VERSION 5.7 ;
  NOWIREEXTENSIONATPIN ON ;
  DIVIDERCHAR "/" ;
  BUSBITCHARS "[]" ;
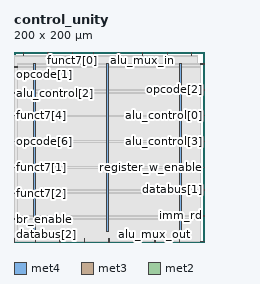
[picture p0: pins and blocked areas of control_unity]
MACRO control_unity
  CLASS BLOCK ;
  FOREIGN control_unity ;
  ORIGIN 0.000 0.000 ;
  SIZE 200.000 BY 200.000 ;
  PIN VGND
    USE GROUND ;
    PORT
      LAYER met4 ;
        RECT 97.840 10.640 99.440 187.920 ;
    END
  END VGND
  PIN VPWR
    USE POWER ;
    PORT
      LAYER met4 ;
        RECT 174.640 10.640 176.240 187.920 ;
    END
    PORT
      LAYER met4 ;
        RECT 21.040 10.640 22.640 187.920 ;
    END
  END VPWR
  PIN alu_control[0]
    PORT
      LAYER met3 ;
        RECT 196.000 132.640 200.000 133.240 ;
    END
  END alu_control[0]
  PIN alu_control[1]
    PORT
      LAYER met2 ;
        RECT 99.910 0.000 100.190 4.000 ;
    END
  END alu_control[1]
  PIN alu_control[2]
    PORT
      LAYER met3 ;
        RECT 0.000 156.440 4.000 157.040 ;
    END
  END alu_control[2]
  PIN alu_control[3]
    PORT
      LAYER met3 ;
        RECT 196.000 105.440 200.000 106.040 ;
    END
  END alu_control[3]
  PIN alu_mux_in
    PORT
      LAYER met2 ;
        RECT 135.330 196.000 135.610 200.000 ;
    END
  END alu_mux_in
  PIN alu_mux_out
    PORT
      LAYER met2 ;
        RECT 148.210 0.000 148.490 4.000 ;
    END
  END alu_mux_out
  PIN br_enable
    PORT
      LAYER met3 ;
        RECT 0.000 23.840 4.000 24.440 ;
    END
  END br_enable
  PIN br_mux_inv
    PORT
      LAYER met3 ;
        RECT 196.000 187.040 200.000 187.640 ;
    END
  END br_mux_inv
  PIN databus[0]
    PORT
      LAYER met2 ;
        RECT 161.090 196.000 161.370 200.000 ;
    END
  END databus[0]
  PIN databus[1]
    PORT
      LAYER met3 ;
        RECT 196.000 54.440 200.000 55.040 ;
    END
  END databus[1]
  PIN databus[2]
    PORT
      LAYER met2 ;
        RECT 0.090 0.000 0.370 4.000 ;
    END
  END databus[2]
  PIN funct3[0]
    PORT
      LAYER met2 ;
        RECT 173.970 0.000 174.250 4.000 ;
    END
  END funct3[0]
  PIN funct3[1]
    PORT
      LAYER met2 ;
        RECT 186.850 196.000 187.130 200.000 ;
    END
  END funct3[1]
  PIN funct3[2]
    PORT
      LAYER met2 ;
        RECT 48.390 0.000 48.670 4.000 ;
    END
  END funct3[2]
  PIN funct7[0]
    PORT
      LAYER met2 ;
        RECT 61.270 196.000 61.550 200.000 ;
    END
  END funct7[0]
  PIN funct7[1]
    PORT
      LAYER met3 ;
        RECT 0.000 78.240 4.000 78.840 ;
    END
  END funct7[1]
  PIN funct7[2]
    PORT
      LAYER met3 ;
        RECT 0.000 51.040 4.000 51.640 ;
    END
  END funct7[2]
  PIN funct7[3]
    PORT
      LAYER met3 ;
        RECT 196.000 0.040 200.000 0.640 ;
    END
  END funct7[3]
  PIN funct7[4]
    PORT
      LAYER met3 ;
        RECT 0.000 132.640 4.000 133.240 ;
    END
  END funct7[4]
  PIN funct7[5]
    PORT
      LAYER met2 ;
        RECT 22.630 0.000 22.910 4.000 ;
    END
  END funct7[5]
  PIN funct7[6]
    PORT
      LAYER met2 ;
        RECT 35.510 196.000 35.790 200.000 ;
    END
  END funct7[6]
  PIN imm_rd
    PORT
      LAYER met3 ;
        RECT 196.000 27.240 200.000 27.840 ;
    END
  END imm_rd
  PIN opcode[0]
    PORT
      LAYER met2 ;
        RECT 74.150 0.000 74.430 4.000 ;
    END
  END opcode[0]
  PIN opcode[1]
    PORT
      LAYER met3 ;
        RECT 0.000 183.640 4.000 184.240 ;
    END
  END opcode[1]
  PIN opcode[2]
    PORT
      LAYER met3 ;
        RECT 196.000 159.840 200.000 160.440 ;
    END
  END opcode[2]
  PIN opcode[3]
    PORT
      LAYER met2 ;
        RECT 83.810 196.000 84.090 200.000 ;
    END
  END opcode[3]
  PIN opcode[4]
    PORT
      LAYER met2 ;
        RECT 109.570 196.000 109.850 200.000 ;
    END
  END opcode[4]
  PIN opcode[5]
    PORT
      LAYER met2 ;
        RECT 125.670 0.000 125.950 4.000 ;
    END
  END opcode[5]
  PIN opcode[6]
    PORT
      LAYER met3 ;
        RECT 0.000 105.440 4.000 106.040 ;
    END
  END opcode[6]
  PIN ram_w_enable
    PORT
      LAYER met2 ;
        RECT 9.750 196.000 10.030 200.000 ;
    END
  END ram_w_enable
  PIN register_w_enable
    PORT
      LAYER met3 ;
        RECT 196.000 78.240 200.000 78.840 ;
    END
  END register_w_enable
  OBS
      LAYER li1 ;
        RECT 5.520 10.795 194.120 187.765 ;
      LAYER met1 ;
        RECT 0.070 10.640 194.120 187.920 ;
      LAYER met2 ;
        RECT 0.100 195.720 9.470 196.000 ;
        RECT 10.310 195.720 35.230 196.000 ;
        RECT 36.070 195.720 60.990 196.000 ;
        RECT 61.830 195.720 83.530 196.000 ;
        RECT 84.370 195.720 109.290 196.000 ;
        RECT 110.130 195.720 135.050 196.000 ;
        RECT 135.890 195.720 160.810 196.000 ;
        RECT 161.650 195.720 186.570 196.000 ;
        RECT 187.410 195.720 192.650 196.000 ;
        RECT 0.100 4.280 192.650 195.720 ;
        RECT 0.650 0.155 22.350 4.280 ;
        RECT 23.190 0.155 48.110 4.280 ;
        RECT 48.950 0.155 73.870 4.280 ;
        RECT 74.710 0.155 99.630 4.280 ;
        RECT 100.470 0.155 125.390 4.280 ;
        RECT 126.230 0.155 147.930 4.280 ;
        RECT 148.770 0.155 173.690 4.280 ;
        RECT 174.530 0.155 192.650 4.280 ;
      LAYER met3 ;
        RECT 4.000 186.640 195.600 187.845 ;
        RECT 4.000 184.640 196.000 186.640 ;
        RECT 4.400 183.240 196.000 184.640 ;
        RECT 4.000 160.840 196.000 183.240 ;
        RECT 4.000 159.440 195.600 160.840 ;
        RECT 4.000 157.440 196.000 159.440 ;
        RECT 4.400 156.040 196.000 157.440 ;
        RECT 4.000 133.640 196.000 156.040 ;
        RECT 4.400 132.240 195.600 133.640 ;
        RECT 4.000 106.440 196.000 132.240 ;
        RECT 4.400 105.040 195.600 106.440 ;
        RECT 4.000 79.240 196.000 105.040 ;
        RECT 4.400 77.840 195.600 79.240 ;
        RECT 4.000 55.440 196.000 77.840 ;
        RECT 4.000 54.040 195.600 55.440 ;
        RECT 4.000 52.040 196.000 54.040 ;
        RECT 4.400 50.640 196.000 52.040 ;
        RECT 4.000 28.240 196.000 50.640 ;
        RECT 4.000 26.840 195.600 28.240 ;
        RECT 4.000 24.840 196.000 26.840 ;
        RECT 4.400 23.440 196.000 24.840 ;
        RECT 4.000 1.040 196.000 23.440 ;
        RECT 4.000 0.175 195.600 1.040 ;
  END
END control_unity
END LIBRARY

